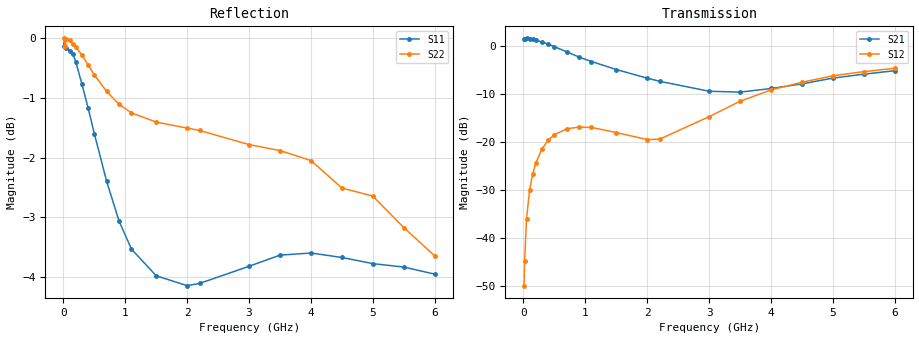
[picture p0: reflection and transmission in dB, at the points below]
! Infineon Technologies  Discrete & RF Semiconductors
! BFS17W
! Si NPN RF Bipolar Junction Transistor in SOT323
! VCE = 10 V  IC = 0.3 mA
! Common Emitter S-Parameters:  August  1999
# GHz  S  MA  R  50
!  f  S11  S21  S12  S22
! GHz  MAG  ANG  MAG  ANG  MAG  ANG  MAG  ANG
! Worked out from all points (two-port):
!   36 points, 10 MHz to 6 GHz, reference 50 ohm
!   highest |S21| = 1.55 dB at 50 MHz (marker M1); lowest = -9.6 dB at 3.5 GHz (marker M2)
!   |S21| within 3 dB of the highest: start of sweep to 737.1 MHz
!   lowest |S11| = -4.1 dB at 2 GHz (marker M3), VSWR 4.27, Z = 11.7 + j1.82 ohm
!   |S11| at or under -10 dB: nowhere
!   |S22| runs from -3.6 to 0.0 dB; largest |S21 - S12| = 1.2
!   S11 on the Smith chart (normalised r, x): 10 MHz: 36, -61; 300 MHz: 0.28, -2.30; 700 MHz: 0.24, -0.87; 1.5 GHz: 0.23, -0.18; 3 GHz: 0.25, +0.37; 6 GHz: 0.54, +1.11
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0.01  0.9859 -1.4  1.19 179.5  0.0032 89.1  0.9999 0.1
0.02  0.9992 -3.5  1.192 177.4  0.0058 89.9  0.9845 -0.6
0.05  0.9819 -8.0  1.196 173.3  0.0157 86.7  0.9982 -1.9
0.1  0.9759 -15.7  1.174 167.0  0.0316 80.2  0.9964 -3.9
0.15  0.9711 -24.3  1.168 160.1  0.0464 75.0  0.9894 -5.8
0.2  0.9561 -31.5  1.147 153.7  0.0606 71.0  0.9832 -7.6
0.3  0.9153 -46.4  1.096 141.3  0.0846 62.5  0.968 -11.0
0.4  0.8742 -60.3  1.043 129.7  0.1046 54.6  0.9499 -14.2
0.5  0.8321 -73.2  0.98 119.5  0.1189 47.8  0.9318 -17.0
0.7  0.7585 -96.2  0.866 101.6  0.137 37.6  0.9025 -21.9
0.9  0.7026 -115.1  0.764 87.3  0.1429 30.0  0.8803 -26.6
1.1  0.6657 -131.8  0.687 75.0  0.1417 25.4  0.8659 -31.2
1.5  0.6323 -158.6  0.567 57.1  0.1253 23.3  0.8507 -40.6
2  0.6203 175.6  0.461 42.6  0.106 37.0  0.8408 -53.4
2.2  0.623 167.0  0.428 38.8  0.1069 47.2  0.837 -58.7
3  0.644 137.0  0.337 35.9  0.1834 73.6  0.8145 -80.6
3.5  0.658 121.6  0.33 40.5  0.265 73.1  0.8052 -95.1
4  0.6607 108.8  0.36 44.2  0.348 67.2  0.7898 -110.7
4.5  0.655 97.8  0.402 44.4  0.4179 59.7  0.749 -125.8
5  0.6473 89.3  0.462 41.6  0.4882 52.0  0.7374 -139.6
5.5  0.643 82.2  0.507 37.3  0.5392 44.4  0.6939 -153.8
6  0.6343 76.6  0.551 32.4  0.5838 37.4  0.657 -166.2
